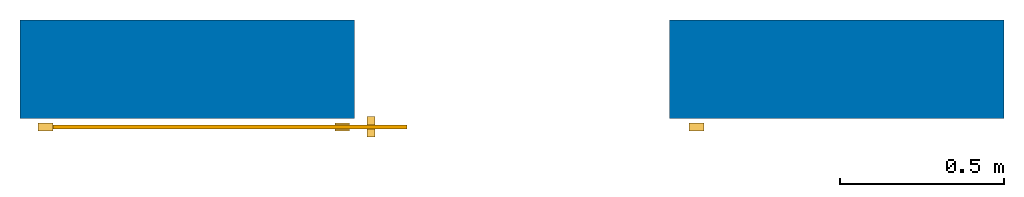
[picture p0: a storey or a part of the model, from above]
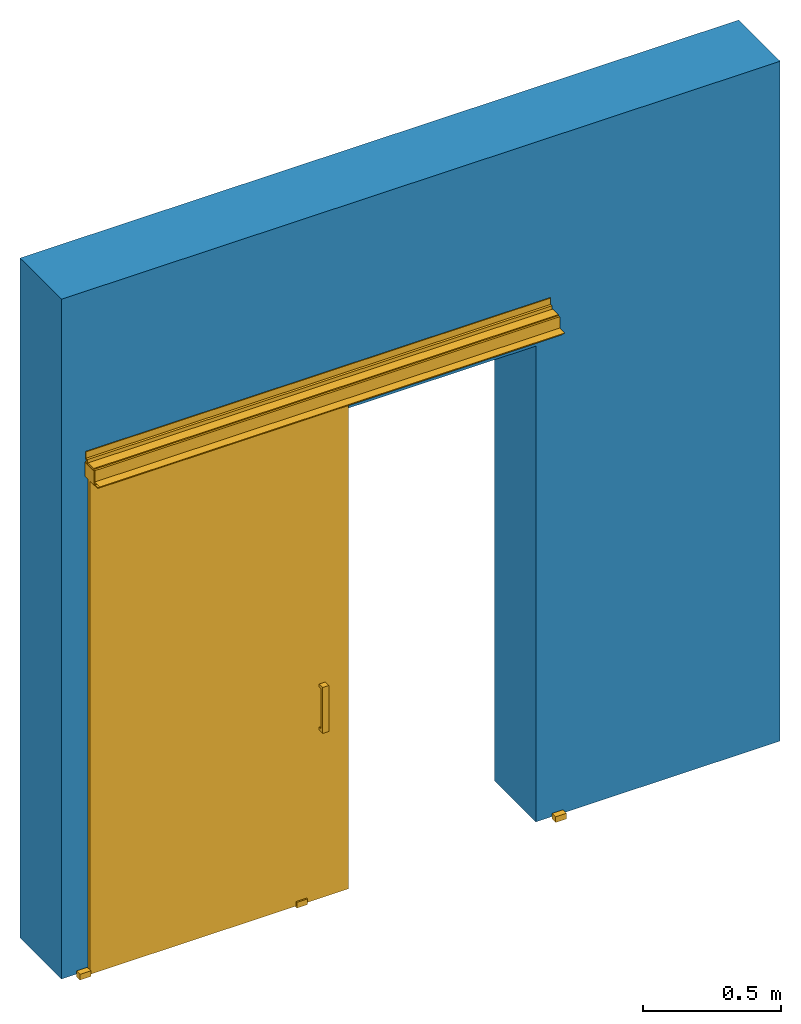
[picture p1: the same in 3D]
Properties of the parts of a building model (IFC2X3)

# File
Description: ViewDefinition [CoordinationView_V2.0]
File name: Número de proyecto
Time: 2017-11-13T15:23:07
Written by: The EXPRESS Data Manager Version 5.02.0100.07 : 28 Aug 2013
Made in: 20160512_1515(x64) - Exporter 15.6.0.0 - Alternate UI 15.6.0.0
Comment: STEP Physical File produced by: The EXPRESS Data Manager Version 5.02.0100.07 : 28 Aug 2013 * Module: EDMstepFileFactory/EDMstandAlone * Creation date: Mon Nov 13 15:23:07 2017 * Host: MSI * Database: C:\Users\TUMADR~1\AppData\Local\Temp\{674819BB-71A5-4191-8D3C-19EB85682904}\ifc * Database version: 5507 * Database creation date: Mon Nov 13 15:23:07 2017 * Schema: IFC2X3 * Model: DataRepository.ifc * Model creation date: Mon Nov 13 15:23:07 2017 * Header model: DataRepository.ifc_HeaderModel * Header model creation date: Mon Nov 13 15:23:07 2017 * EDMuser: sdai-user * EDMgroup: sdai-group * License ID and type: 5605 : Permanent license. Expiry date: * EDMstepFileFactory options: 020000

# IfcProject, Número de proyecto
LongName: Nombre de proyecto; Phase: Estado de proyecto

# IfcSite, Default
RefLatitude: 40, 25, 0, 86975; RefLongitude: -3, -42, -1, -243858; RefElevation: 0 m
Other - Category: Project Information; Client Name: Propietario; Project Address: Introduzca dirección aquí; Project Issue Date: Fecha de emisión; Project Name: Nombre de proyecto; Project Number: Número de proyecto; Project Status: Estado de proyecto

# IfcBuilding
Pset_BuildingCommon - NumberOfStoreys: 1
Other - Category: Project Information; Client Name: Propietario; Project Address: Introduzca dirección aquí; Project Issue Date: Fecha de emisión; Project Name: Nombre de proyecto; Project Number: Número de proyecto; Project Status: Estado de proyecto

# IfcBuildingStorey, Nivel 1
LongName: Nivel 1; Elevation: 0 m
Constraints - Elevation: 0 m; Elevation Base: Project Base Point
Dimensions - Computation Height: 0 m
Identity Data - Structural: no; Building Story: yes; Name: Nivel 1; Type Name: Nivel 1
Other - Category: Levels; Family: Level: Nivel 1; Family and Type: Level: Nivel 1; Type: Level: Nivel 1; Type Id: Level: Nivel 1; Family Name: Level
Graphics - Color: 0; Line Pattern: Trazo punto; Line Weight: 1; Symbol: Extremo de nivel: Extremo de nivel; Symbol at End 1 Default: no; Symbol at End 2 Default: yes

# IfcDoor: Default, EU-2015_Door_Klein_Unikglass+_Sliding:Default:152321
In: Nivel 1
Type - ParameterTakesPrecedence: no; Sizeable: no; Material: Aluminium, Anodized Silver, Acetal Resin, White, Glass
Type - Analysis Results - SurfaceMass: 0
Type - Analytical Properties - Analytic Construction: <None>
Type - Construction - IsExternal: no; HandicapAccessible: no; FireExit: no; SmokeStop: no; Function: Interior; HasDrive: no; Wall Closure: By host
Type - Data - GlazingAreaFraction: 1
Type - Dimensions - ExteriorOffset: 0 m; Handle Height: 0.85 m; Height: 2.1 m; InteriorOffset: 0 m; Rough Height: 0 m; Rough Width: 1.07 m; Thickness: 0 m; Width: 0.96 m
Type - General - IFCClassification: IfcDoor; MasterformatCode: 08 12 16; MasterformatTitle: Aluminum Frames; OmniclassCode: 23-17 11 23 13; OmniclassTitle: Sliding All Glass Doors; Uniclass2.0Code: 30-59-23-02; Uniclass2.0Title: Aluminium door frames; UNSPSCCode: 30162306; UNSPSCTitle: Door mount or sliding towel hardware or assembly
Type - Green Building Properties - EmbodiedCarbon: 0; EnergeticCostKw·h: 0; EnergeticCostMJ: 0; RawMaterial: 0
Type - Identity Data - Author: Bimetica Parametric Design Services S.L.; BIMElementExpiryDate: 09/11/2018; BIMElementIssueDate: 09/11/2017; BIMElementVersion: V01; Bimetica: www.bimetica.com; ContactEmail: bim@klein.es; ContactReference: Technical Department; ContactTelephone: (+34) 935 760 101; Description: Sliding Glass Door; Manufacturer: Klein; Model: Unikglass+; OmniClass Number: 23.30.10.17.11; OmniClass Title: Sliding Doors; ProductURL: http://www.klein-europe.com/en/products/unikglass; Reference: UNIKGLASS+; TechnicalInformation: http://www.klein-europe.com/en/products/unikglass; Type Comments: Door maximum weight up to 50Kg for Unikglass+ 50, and up to 100Kg for Unikglass+ 100. All glass dimensions must be checked with KLEIN mounting instructions. The system is available in Silver, Black or Dark Bronze anodized finish. KSC optional (Klein Soft Closing) for a smooth and controlled closing for glass width starting at 800mm. Check the feasibility of the system on our Website.; Type Mark: 7; Type Name: Default; URL: http://www.klein-europe.com
Type - Materials and Finishes - End Caps: Acetal Resin, White; Frame Material: Aluminium, Anodized Silver; Panel Material: Glass
Type - Other - Category: Doors; Family Name: EU-2015_Door_Klein_Unikglass+_Sliding; MaintenanceCost: 0
OverallHeight: 2.1 m; OverallWidth: 0.96 m
Pset_DoorCommon - Reference: UNIKGLASS+; IsExternal: no; HandicapAccessible: no; FireExit: no; SmokeStop: no; GlazingAreaFraction: 1
Pset_ManufacturerTypeInformation - Manufacturer: Klein
Constraints - Central Door: yes; Door Against Wall: no; Level: Level: Nivel 1; Recessed Installation with Lintel: no; Recessed Installation without Lintel: yes; Sill Height: 0 m
Construction - Handle Type: U Handle
Dimensions - A: 0.1 m; Area: 2.67183 m2; Clear Opening: 0.8 m; Guide Stop: 0.06 m; Opening: 0.86 m; Panel Thickness: 0.012 m; Panel Width: 1.08 m; Perimeter: 6560; Track Length: 1.88 m; True Opening: 0.86 m; True Thickness: 0.012 m; Volume: 0.0365508 m3
Division Geometry - Aperture: 1
Identity Data - Mark: 1
Other - Family: EU-2015_Door_Klein_Unikglass+_Sliding: Default; Family and Type: EU-2015_Door_Klein_Unikglass+_Sliding: Default; Head Height: 2.1 m; Host Id: Basic Wall: Por defecto - 30 cm; True Recessed Installation: yes; Type: EU-2015_Door_Klein_Unikglass+_Sliding: Default; Type Id: EU-2015_Door_Klein_Unikglass+_Sliding: Default
Phasing - Phase Created: Nueva construcción

# IfcWallStandardCase: Basic Wall:Por defecto - 30 cm, Basic Wall:Por defecto - 30 cm:150189
In: Nivel 1
Type - PredefinedType: STANDARD; Material: Muro por defecto 0.3 m
Type - Analytical Properties - Absorptance: 0.7; Roughness: 3
Type - Construction - Function: Exterior; Width: 0.3 m; Wrapping at Inserts: Do not wrap
Type - Graphics - Coarse Scale Fill Color: 0
Type - Identity Data - Keynote: Md.1; Type Name: Por defecto - 30 cm
Type - Other - Category: Walls; Family Name: Basic Wall
Constraints - Base Constraint: Level: Nivel 1; Base Extension Distance: 0 m; Base is Attached: no; Base Offset: 0 m; Location Line: Core Face: Exterior; Related to Mass: no; Room Bounding: yes; Top Constraint: Level: Nivel 2; Top Extension Distance: 0 m; Top is Attached: no; Top Offset: 0 m; Unconnected Height: 3 m
Dimensions - Area: 6.984 m2; Length: 3 m; Volume: 2.0952 m3
Other - Family: Basic Wall: Por defecto - 30 cm; Family and Type: Basic Wall: Por defecto - 30 cm; Type: Basic Wall: Por defecto - 30 cm; Type Id: Basic Wall: Por defecto - 30 cm
Phasing - Phase Created: Nueva construcción
Structural - Enable Analytical Model: no; Structural: no; Structural Usage: Non-bearing
Pset_WallCommon - Reference: Basic Wall:Por defecto - 30 cm; LoadBearing: no; ExtendToStructure: no; IsExternal: yes
